VERSION 5.8 ;
NAMESCASESENSITIVE ON ;
BUSBITCHARS "[]" ;
DIVIDERCHAR "/" ;
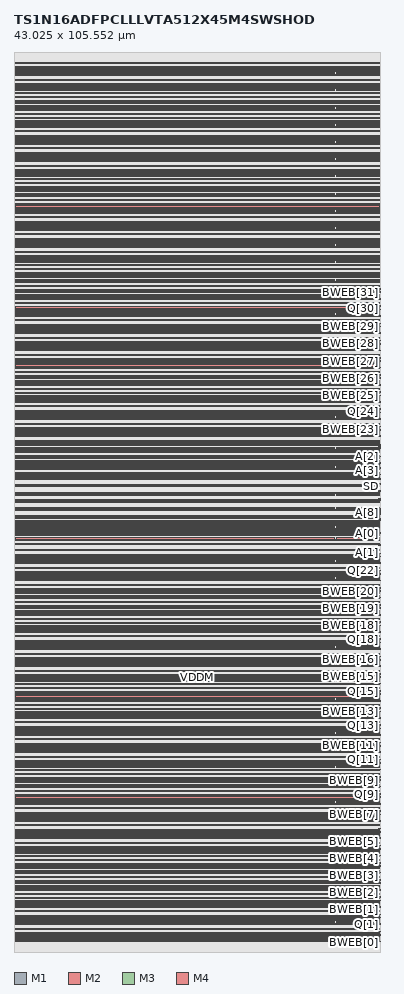
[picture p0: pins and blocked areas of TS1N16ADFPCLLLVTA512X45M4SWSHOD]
MACRO TS1N16ADFPCLLLVTA512X45M4SWSHOD
	CLASS BLOCK ;
	FOREIGN TS1N16ADFPCLLLVTA512X45M4SWSHOD 0.0 0.0 ;
	ORIGIN 0.0 0.0 ;
	SIZE 43.025 BY 105.552 ;
	SYMMETRY X Y ;
	PIN A[0]
		DIRECTION INPUT ;
		USE SIGNAL ;
		PORT
			LAYER M1 ;
			RECT 42.777 49.064 43.025 49.144 ;
			LAYER M2 ;
			RECT 42.777 49.064 43.025 49.144 ;
			LAYER M3 ;
			RECT 42.777 49.064 43.025 49.144 ;
		END
	END A[0]

	PIN A[1]
		DIRECTION INPUT ;
		USE SIGNAL ;
		PORT
			LAYER M1 ;
			RECT 42.777 47.720 43.025 47.800 ;
			LAYER M2 ;
			RECT 42.777 47.720 43.025 47.800 ;
			LAYER M3 ;
			RECT 42.777 47.720 43.025 47.800 ;
		END
	END A[1]

	PIN A[2]
		DIRECTION INPUT ;
		USE SIGNAL ;
		PORT
			LAYER M1 ;
			RECT 42.777 58.088 43.025 58.168 ;
			LAYER M2 ;
			RECT 42.777 58.088 43.025 58.168 ;
			LAYER M3 ;
			RECT 42.777 58.088 43.025 58.168 ;
		END
	END A[2]

	PIN A[3]
		DIRECTION INPUT ;
		USE SIGNAL ;
		PORT
			LAYER M1 ;
			RECT 42.777 57.320 43.025 57.400 ;
			LAYER M2 ;
			RECT 42.777 57.320 43.025 57.400 ;
			LAYER M3 ;
			RECT 42.777 57.320 43.025 57.400 ;
		END
	END A[3]

	PIN A[4]
		DIRECTION INPUT ;
		USE SIGNAL ;
		PORT
			LAYER M1 ;
			RECT 42.777 56.744 43.025 56.824 ;
			LAYER M2 ;
			RECT 42.777 56.744 43.025 56.824 ;
			LAYER M3 ;
			RECT 42.777 56.744 43.025 56.824 ;
		END
	END A[4]

	PIN A[5]
		DIRECTION INPUT ;
		USE SIGNAL ;
		PORT
			LAYER M1 ;
			RECT 42.777 54.056 43.025 54.136 ;
			LAYER M2 ;
			RECT 42.777 54.056 43.025 54.136 ;
			LAYER M3 ;
			RECT 42.777 54.056 43.025 54.136 ;
		END
	END A[5]

	PIN A[6]
		DIRECTION INPUT ;
		USE SIGNAL ;
		PORT
			LAYER M1 ;
			RECT 42.777 54.824 43.025 54.904 ;
			LAYER M2 ;
			RECT 42.777 54.824 43.025 54.904 ;
			LAYER M3 ;
			RECT 42.777 54.824 43.025 54.904 ;
		END
	END A[6]

	PIN A[7]
		DIRECTION INPUT ;
		USE SIGNAL ;
		PORT
			LAYER M1 ;
			RECT 42.777 55.976 43.025 56.056 ;
			LAYER M2 ;
			RECT 42.777 55.976 43.025 56.056 ;
			LAYER M3 ;
			RECT 42.777 55.976 43.025 56.056 ;
		END
	END A[7]

	PIN A[8]
		DIRECTION INPUT ;
		USE SIGNAL ;
		PORT
			LAYER M1 ;
			RECT 42.777 50.600 43.025 50.680 ;
			LAYER M2 ;
			RECT 42.777 50.600 43.025 50.680 ;
			LAYER M3 ;
			RECT 42.777 50.600 43.025 50.680 ;
		END
	END A[8]

	PIN BWEB[0]
		DIRECTION INPUT ;
		USE SIGNAL ;
		PORT
			LAYER M1 ;
			RECT 42.777 1.976 43.025 2.056 ;
			LAYER M2 ;
			RECT 42.777 1.976 43.025 2.056 ;
			LAYER M3 ;
			RECT 42.777 1.976 43.025 2.056 ;
		END
	END BWEB[0]

	PIN BWEB[1]
		DIRECTION INPUT ;
		USE SIGNAL ;
		PORT
			LAYER M1 ;
			RECT 42.777 3.992 43.025 4.072 ;
			LAYER M2 ;
			RECT 42.777 3.992 43.025 4.072 ;
			LAYER M3 ;
			RECT 42.777 3.992 43.025 4.072 ;
		END
	END BWEB[1]

	PIN BWEB[2]
		DIRECTION INPUT ;
		USE SIGNAL ;
		PORT
			LAYER M1 ;
			RECT 42.777 6.008 43.025 6.088 ;
			LAYER M2 ;
			RECT 42.777 6.008 43.025 6.088 ;
			LAYER M3 ;
			RECT 42.777 6.008 43.025 6.088 ;
		END
	END BWEB[2]

	PIN BWEB[3]
		DIRECTION INPUT ;
		USE SIGNAL ;
		PORT
			LAYER M1 ;
			RECT 42.777 8.024 43.025 8.104 ;
			LAYER M2 ;
			RECT 42.777 8.024 43.025 8.104 ;
			LAYER M3 ;
			RECT 42.777 8.024 43.025 8.104 ;
		END
	END BWEB[3]

	PIN BWEB[4]
		DIRECTION INPUT ;
		USE SIGNAL ;
		PORT
			LAYER M1 ;
			RECT 42.777 10.040 43.025 10.120 ;
			LAYER M2 ;
			RECT 42.777 10.040 43.025 10.120 ;
			LAYER M3 ;
			RECT 42.777 10.040 43.025 10.120 ;
		END
	END BWEB[4]

	PIN BWEB[5]
		DIRECTION INPUT ;
		USE SIGNAL ;
		PORT
			LAYER M1 ;
			RECT 42.777 12.056 43.025 12.136 ;
			LAYER M2 ;
			RECT 42.777 12.056 43.025 12.136 ;
			LAYER M3 ;
			RECT 42.777 12.056 43.025 12.136 ;
		END
	END BWEB[5]

	PIN BWEB[6]
		DIRECTION INPUT ;
		USE SIGNAL ;
		PORT
			LAYER M1 ;
			RECT 42.777 14.072 43.025 14.152 ;
			LAYER M2 ;
			RECT 42.777 14.072 43.025 14.152 ;
			LAYER M3 ;
			RECT 42.777 14.072 43.025 14.152 ;
		END
	END BWEB[6]

	PIN BWEB[7]
		DIRECTION INPUT ;
		USE SIGNAL ;
		PORT
			LAYER M1 ;
			RECT 42.777 16.088 43.025 16.168 ;
			LAYER M2 ;
			RECT 42.777 16.088 43.025 16.168 ;
			LAYER M3 ;
			RECT 42.777 16.088 43.025 16.168 ;
		END
	END BWEB[7]

	PIN BWEB[8]
		DIRECTION INPUT ;
		USE SIGNAL ;
		PORT
			LAYER M1 ;
			RECT 42.777 18.104 43.025 18.184 ;
			LAYER M2 ;
			RECT 42.777 18.104 43.025 18.184 ;
			LAYER M3 ;
			RECT 42.777 18.104 43.025 18.184 ;
		END
	END BWEB[8]

	PIN BWEB[9]
		DIRECTION INPUT ;
		USE SIGNAL ;
		PORT
			LAYER M1 ;
			RECT 42.777 20.120 43.025 20.200 ;
			LAYER M2 ;
			RECT 42.777 20.120 43.025 20.200 ;
			LAYER M3 ;
			RECT 42.777 20.120 43.025 20.200 ;
		END
	END BWEB[9]

	PIN BWEB[10]
		DIRECTION INPUT ;
		USE SIGNAL ;
		PORT
			LAYER M1 ;
			RECT 42.777 22.136 43.025 22.216 ;
			LAYER M2 ;
			RECT 42.777 22.136 43.025 22.216 ;
			LAYER M3 ;
			RECT 42.777 22.136 43.025 22.216 ;
		END
	END BWEB[10]

	PIN BWEB[11]
		DIRECTION INPUT ;
		USE SIGNAL ;
		PORT
			LAYER M1 ;
			RECT 42.777 24.152 43.025 24.232 ;
			LAYER M2 ;
			RECT 42.777 24.152 43.025 24.232 ;
			LAYER M3 ;
			RECT 42.777 24.152 43.025 24.232 ;
		END
	END BWEB[11]

	PIN BWEB[12]
		DIRECTION INPUT ;
		USE SIGNAL ;
		PORT
			LAYER M1 ;
			RECT 42.777 26.168 43.025 26.248 ;
			LAYER M2 ;
			RECT 42.777 26.168 43.025 26.248 ;
			LAYER M3 ;
			RECT 42.777 26.168 43.025 26.248 ;
		END
	END BWEB[12]

	PIN BWEB[13]
		DIRECTION INPUT ;
		USE SIGNAL ;
		PORT
			LAYER M1 ;
			RECT 42.777 28.184 43.025 28.264 ;
			LAYER M2 ;
			RECT 42.777 28.184 43.025 28.264 ;
			LAYER M3 ;
			RECT 42.777 28.184 43.025 28.264 ;
		END
	END BWEB[13]

	PIN BWEB[14]
		DIRECTION INPUT ;
		USE SIGNAL ;
		PORT
			LAYER M1 ;
			RECT 42.777 30.200 43.025 30.280 ;
			LAYER M2 ;
			RECT 42.777 30.200 43.025 30.280 ;
			LAYER M3 ;
			RECT 42.777 30.200 43.025 30.280 ;
		END
	END BWEB[14]

	PIN BWEB[15]
		DIRECTION INPUT ;
		USE SIGNAL ;
		PORT
			LAYER M1 ;
			RECT 42.777 32.216 43.025 32.296 ;
			LAYER M2 ;
			RECT 42.777 32.216 43.025 32.296 ;
			LAYER M3 ;
			RECT 42.777 32.216 43.025 32.296 ;
		END
	END BWEB[15]

	PIN BWEB[16]
		DIRECTION INPUT ;
		USE SIGNAL ;
		PORT
			LAYER M1 ;
			RECT 42.777 34.232 43.025 34.312 ;
			LAYER M2 ;
			RECT 42.777 34.232 43.025 34.312 ;
			LAYER M3 ;
			RECT 42.777 34.232 43.025 34.312 ;
		END
	END BWEB[16]

	PIN BWEB[17]
		DIRECTION INPUT ;
		USE SIGNAL ;
		PORT
			LAYER M1 ;
			RECT 42.777 36.248 43.025 36.328 ;
			LAYER M2 ;
			RECT 42.777 36.248 43.025 36.328 ;
			LAYER M3 ;
			RECT 42.777 36.248 43.025 36.328 ;
		END
	END BWEB[17]

	PIN BWEB[18]
		DIRECTION INPUT ;
		USE SIGNAL ;
		PORT
			LAYER M1 ;
			RECT 42.777 38.264 43.025 38.344 ;
			LAYER M2 ;
			RECT 42.777 38.264 43.025 38.344 ;
			LAYER M3 ;
			RECT 42.777 38.264 43.025 38.344 ;
		END
	END BWEB[18]

	PIN BWEB[19]
		DIRECTION INPUT ;
		USE SIGNAL ;
		PORT
			LAYER M1 ;
			RECT 42.777 40.280 43.025 40.360 ;
			LAYER M2 ;
			RECT 42.777 40.280 43.025 40.360 ;
			LAYER M3 ;
			RECT 42.777 40.280 43.025 40.360 ;
		END
	END BWEB[19]

	PIN BWEB[20]
		DIRECTION INPUT ;
		USE SIGNAL ;
		PORT
			LAYER M1 ;
			RECT 42.777 42.296 43.025 42.376 ;
			LAYER M2 ;
			RECT 42.777 42.296 43.025 42.376 ;
			LAYER M3 ;
			RECT 42.777 42.296 43.025 42.376 ;
		END
	END BWEB[20]

	PIN BWEB[21]
		DIRECTION INPUT ;
		USE SIGNAL ;
		PORT
			LAYER M1 ;
			RECT 42.777 44.312 43.025 44.392 ;
			LAYER M2 ;
			RECT 42.777 44.312 43.025 44.392 ;
			LAYER M3 ;
			RECT 42.777 44.312 43.025 44.392 ;
		END
	END BWEB[21]

	PIN BWEB[22]
		DIRECTION INPUT ;
		USE SIGNAL ;
		PORT
			LAYER M1 ;
			RECT 42.777 46.328 43.025 46.408 ;
			LAYER M2 ;
			RECT 42.777 46.328 43.025 46.408 ;
			LAYER M3 ;
			RECT 42.777 46.328 43.025 46.408 ;
		END
	END BWEB[22]

	PIN BWEB[23]
		DIRECTION INPUT ;
		USE SIGNAL ;
		PORT
			LAYER M1 ;
			RECT 42.777 61.208 43.025 61.288 ;
			LAYER M2 ;
			RECT 42.777 61.208 43.025 61.288 ;
			LAYER M3 ;
			RECT 42.777 61.208 43.025 61.288 ;
		END
	END BWEB[23]

	PIN BWEB[24]
		DIRECTION INPUT ;
		USE SIGNAL ;
		PORT
			LAYER M1 ;
			RECT 42.777 63.224 43.025 63.304 ;
			LAYER M2 ;
			RECT 42.777 63.224 43.025 63.304 ;
			LAYER M3 ;
			RECT 42.777 63.224 43.025 63.304 ;
		END
	END BWEB[24]

	PIN BWEB[25]
		DIRECTION INPUT ;
		USE SIGNAL ;
		PORT
			LAYER M1 ;
			RECT 42.777 65.240 43.025 65.320 ;
			LAYER M2 ;
			RECT 42.777 65.240 43.025 65.320 ;
			LAYER M3 ;
			RECT 42.777 65.240 43.025 65.320 ;
		END
	END BWEB[25]

	PIN BWEB[26]
		DIRECTION INPUT ;
		USE SIGNAL ;
		PORT
			LAYER M1 ;
			RECT 42.777 67.256 43.025 67.336 ;
			LAYER M2 ;
			RECT 42.777 67.256 43.025 67.336 ;
			LAYER M3 ;
			RECT 42.777 67.256 43.025 67.336 ;
		END
	END BWEB[26]

	PIN BWEB[27]
		DIRECTION INPUT ;
		USE SIGNAL ;
		PORT
			LAYER M1 ;
			RECT 42.777 69.272 43.025 69.352 ;
			LAYER M2 ;
			RECT 42.777 69.272 43.025 69.352 ;
			LAYER M3 ;
			RECT 42.777 69.272 43.025 69.352 ;
		END
	END BWEB[27]

	PIN BWEB[28]
		DIRECTION INPUT ;
		USE SIGNAL ;
		PORT
			LAYER M1 ;
			RECT 42.777 71.288 43.025 71.368 ;
			LAYER M2 ;
			RECT 42.777 71.288 43.025 71.368 ;
			LAYER M3 ;
			RECT 42.777 71.288 43.025 71.368 ;
		END
	END BWEB[28]

	PIN BWEB[29]
		DIRECTION INPUT ;
		USE SIGNAL ;
		PORT
			LAYER M1 ;
			RECT 42.777 73.304 43.025 73.384 ;
			LAYER M2 ;
			RECT 42.777 73.304 43.025 73.384 ;
			LAYER M3 ;
			RECT 42.777 73.304 43.025 73.384 ;
		END
	END BWEB[29]

	PIN BWEB[30]
		DIRECTION INPUT ;
		USE SIGNAL ;
		PORT
			LAYER M1 ;
			RECT 42.777 75.320 43.025 75.400 ;
			LAYER M2 ;
			RECT 42.777 75.320 43.025 75.400 ;
			LAYER M3 ;
			RECT 42.777 75.320 43.025 75.400 ;
		END
	END BWEB[30]

	PIN BWEB[31]
		DIRECTION INPUT ;
		USE SIGNAL ;
		PORT
			LAYER M1 ;
			RECT 42.777 77.336 43.025 77.416 ;
			LAYER M2 ;
			RECT 42.777 77.336 43.025 77.416 ;
			LAYER M3 ;
			RECT 42.777 77.336 43.025 77.416 ;
		END
	END BWEB[31]














	PIN CEB
		DIRECTION INPUT ;
		USE SIGNAL ;
		PORT
			LAYER M1 ;
			RECT 42.777 50.792 43.025 50.872 ;
			LAYER M2 ;
			RECT 42.777 50.792 43.025 50.872 ;
			LAYER M3 ;
			RECT 42.777 50.792 43.025 50.872 ;
		END
	END CEB

	PIN CLK
		DIRECTION INPUT ;
		USE SIGNAL ;
		PORT
			LAYER M1 ;
			RECT 42.777 53.096 43.025 53.176 ;
			LAYER M2 ;
			RECT 42.777 53.096 43.025 53.176 ;
			LAYER M3 ;
			RECT 42.777 53.096 43.025 53.176 ;
		END
	END CLK

	PIN D[0]
		DIRECTION INPUT ;
		USE SIGNAL ;
		PORT
			LAYER M1 ;
			RECT 42.777 2.360 43.025 2.440 ;
			LAYER M2 ;
			RECT 42.777 2.360 43.025 2.440 ;
			LAYER M3 ;
			RECT 42.777 2.360 43.025 2.440 ;
		END
	END D[0]

	PIN D[1]
		DIRECTION INPUT ;
		USE SIGNAL ;
		PORT
			LAYER M1 ;
			RECT 42.777 4.376 43.025 4.456 ;
			LAYER M2 ;
			RECT 42.777 4.376 43.025 4.456 ;
			LAYER M3 ;
			RECT 42.777 4.376 43.025 4.456 ;
		END
	END D[1]

	PIN D[2]
		DIRECTION INPUT ;
		USE SIGNAL ;
		PORT
			LAYER M1 ;
			RECT 42.777 6.392 43.025 6.472 ;
			LAYER M2 ;
			RECT 42.777 6.392 43.025 6.472 ;
			LAYER M3 ;
			RECT 42.777 6.392 43.025 6.472 ;
		END
	END D[2]

	PIN D[3]
		DIRECTION INPUT ;
		USE SIGNAL ;
		PORT
			LAYER M1 ;
			RECT 42.777 8.408 43.025 8.488 ;
			LAYER M2 ;
			RECT 42.777 8.408 43.025 8.488 ;
			LAYER M3 ;
			RECT 42.777 8.408 43.025 8.488 ;
		END
	END D[3]

	PIN D[4]
		DIRECTION INPUT ;
		USE SIGNAL ;
		PORT
			LAYER M1 ;
			RECT 42.777 10.424 43.025 10.504 ;
			LAYER M2 ;
			RECT 42.777 10.424 43.025 10.504 ;
			LAYER M3 ;
			RECT 42.777 10.424 43.025 10.504 ;
		END
	END D[4]

	PIN D[5]
		DIRECTION INPUT ;
		USE SIGNAL ;
		PORT
			LAYER M1 ;
			RECT 42.777 12.440 43.025 12.520 ;
			LAYER M2 ;
			RECT 42.777 12.440 43.025 12.520 ;
			LAYER M3 ;
			RECT 42.777 12.440 43.025 12.520 ;
		END
	END D[5]

	PIN D[6]
		DIRECTION INPUT ;
		USE SIGNAL ;
		PORT
			LAYER M1 ;
			RECT 42.777 14.456 43.025 14.536 ;
			LAYER M2 ;
			RECT 42.777 14.456 43.025 14.536 ;
			LAYER M3 ;
			RECT 42.777 14.456 43.025 14.536 ;
		END
	END D[6]

	PIN D[7]
		DIRECTION INPUT ;
		USE SIGNAL ;
		PORT
			LAYER M1 ;
			RECT 42.777 16.472 43.025 16.552 ;
			LAYER M2 ;
			RECT 42.777 16.472 43.025 16.552 ;
			LAYER M3 ;
			RECT 42.777 16.472 43.025 16.552 ;
		END
	END D[7]

	PIN D[8]
		DIRECTION INPUT ;
		USE SIGNAL ;
		PORT
			LAYER M1 ;
			RECT 42.777 18.488 43.025 18.568 ;
			LAYER M2 ;
			RECT 42.777 18.488 43.025 18.568 ;
			LAYER M3 ;
			RECT 42.777 18.488 43.025 18.568 ;
		END
	END D[8]

	PIN D[9]
		DIRECTION INPUT ;
		USE SIGNAL ;
		PORT
			LAYER M1 ;
			RECT 42.777 20.504 43.025 20.584 ;
			LAYER M2 ;
			RECT 42.777 20.504 43.025 20.584 ;
			LAYER M3 ;
			RECT 42.777 20.504 43.025 20.584 ;
		END
	END D[9]

	PIN D[10]
		DIRECTION INPUT ;
		USE SIGNAL ;
		PORT
			LAYER M1 ;
			RECT 42.777 22.520 43.025 22.600 ;
			LAYER M2 ;
			RECT 42.777 22.520 43.025 22.600 ;
			LAYER M3 ;
			RECT 42.777 22.520 43.025 22.600 ;
		END
	END D[10]

	PIN D[11]
		DIRECTION INPUT ;
		USE SIGNAL ;
		PORT
			LAYER M1 ;
			RECT 42.777 24.536 43.025 24.616 ;
			LAYER M2 ;
			RECT 42.777 24.536 43.025 24.616 ;
			LAYER M3 ;
			RECT 42.777 24.536 43.025 24.616 ;
		END
	END D[11]

	PIN D[12]
		DIRECTION INPUT ;
		USE SIGNAL ;
		PORT
			LAYER M1 ;
			RECT 42.777 26.552 43.025 26.632 ;
			LAYER M2 ;
			RECT 42.777 26.552 43.025 26.632 ;
			LAYER M3 ;
			RECT 42.777 26.552 43.025 26.632 ;
		END
	END D[12]

	PIN D[13]
		DIRECTION INPUT ;
		USE SIGNAL ;
		PORT
			LAYER M1 ;
			RECT 42.777 28.568 43.025 28.648 ;
			LAYER M2 ;
			RECT 42.777 28.568 43.025 28.648 ;
			LAYER M3 ;
			RECT 42.777 28.568 43.025 28.648 ;
		END
	END D[13]

	PIN D[14]
		DIRECTION INPUT ;
		USE SIGNAL ;
		PORT
			LAYER M1 ;
			RECT 42.777 30.584 43.025 30.664 ;
			LAYER M2 ;
			RECT 42.777 30.584 43.025 30.664 ;
			LAYER M3 ;
			RECT 42.777 30.584 43.025 30.664 ;
		END
	END D[14]

	PIN D[15]
		DIRECTION INPUT ;
		USE SIGNAL ;
		PORT
			LAYER M1 ;
			RECT 42.777 32.600 43.025 32.680 ;
			LAYER M2 ;
			RECT 42.777 32.600 43.025 32.680 ;
			LAYER M3 ;
			RECT 42.777 32.600 43.025 32.680 ;
		END
	END D[15]

	PIN D[16]
		DIRECTION INPUT ;
		USE SIGNAL ;
		PORT
			LAYER M1 ;
			RECT 42.777 34.616 43.025 34.696 ;
			LAYER M2 ;
			RECT 42.777 34.616 43.025 34.696 ;
			LAYER M3 ;
			RECT 42.777 34.616 43.025 34.696 ;
		END
	END D[16]

	PIN D[17]
		DIRECTION INPUT ;
		USE SIGNAL ;
		PORT
			LAYER M1 ;
			RECT 42.777 36.632 43.025 36.712 ;
			LAYER M2 ;
			RECT 42.777 36.632 43.025 36.712 ;
			LAYER M3 ;
			RECT 42.777 36.632 43.025 36.712 ;
		END
	END D[17]

	PIN D[18]
		DIRECTION INPUT ;
		USE SIGNAL ;
		PORT
			LAYER M1 ;
			RECT 42.777 38.648 43.025 38.728 ;
			LAYER M2 ;
			RECT 42.777 38.648 43.025 38.728 ;
			LAYER M3 ;
			RECT 42.777 38.648 43.025 38.728 ;
		END
	END D[18]

	PIN D[19]
		DIRECTION INPUT ;
		USE SIGNAL ;
		PORT
			LAYER M1 ;
			RECT 42.777 40.664 43.025 40.744 ;
			LAYER M2 ;
			RECT 42.777 40.664 43.025 40.744 ;
			LAYER M3 ;
			RECT 42.777 40.664 43.025 40.744 ;
		END
	END D[19]

	PIN D[20]
		DIRECTION INPUT ;
		USE SIGNAL ;
		PORT
			LAYER M1 ;
			RECT 42.777 42.680 43.025 42.760 ;
			LAYER M2 ;
			RECT 42.777 42.680 43.025 42.760 ;
			LAYER M3 ;
			RECT 42.777 42.680 43.025 42.760 ;
		END
	END D[20]

	PIN D[21]
		DIRECTION INPUT ;
		USE SIGNAL ;
		PORT
			LAYER M1 ;
			RECT 42.777 44.696 43.025 44.776 ;
			LAYER M2 ;
			RECT 42.777 44.696 43.025 44.776 ;
			LAYER M3 ;
			RECT 42.777 44.696 43.025 44.776 ;
		END
	END D[21]

	PIN D[22]
		DIRECTION INPUT ;
		USE SIGNAL ;
		PORT
			LAYER M1 ;
			RECT 42.777 46.712 43.025 46.792 ;
			LAYER M2 ;
			RECT 42.777 46.712 43.025 46.792 ;
			LAYER M3 ;
			RECT 42.777 46.712 43.025 46.792 ;
		END
	END D[22]

	PIN D[23]
		DIRECTION INPUT ;
		USE SIGNAL ;
		PORT
			LAYER M1 ;
			RECT 42.777 61.592 43.025 61.672 ;
			LAYER M2 ;
			RECT 42.777 61.592 43.025 61.672 ;
			LAYER M3 ;
			RECT 42.777 61.592 43.025 61.672 ;
		END
	END D[23]

	PIN D[24]
		DIRECTION INPUT ;
		USE SIGNAL ;
		PORT
			LAYER M1 ;
			RECT 42.777 63.608 43.025 63.688 ;
			LAYER M2 ;
			RECT 42.777 63.608 43.025 63.688 ;
			LAYER M3 ;
			RECT 42.777 63.608 43.025 63.688 ;
		END
	END D[24]

	PIN D[25]
		DIRECTION INPUT ;
		USE SIGNAL ;
		PORT
			LAYER M1 ;
			RECT 42.777 65.624 43.025 65.704 ;
			LAYER M2 ;
			RECT 42.777 65.624 43.025 65.704 ;
			LAYER M3 ;
			RECT 42.777 65.624 43.025 65.704 ;
		END
	END D[25]

	PIN D[26]
		DIRECTION INPUT ;
		USE SIGNAL ;
		PORT
			LAYER M1 ;
			RECT 42.777 67.640 43.025 67.720 ;
			LAYER M2 ;
			RECT 42.777 67.640 43.025 67.720 ;
			LAYER M3 ;
			RECT 42.777 67.640 43.025 67.720 ;
		END
	END D[26]

	PIN D[27]
		DIRECTION INPUT ;
		USE SIGNAL ;
		PORT
			LAYER M1 ;
			RECT 42.777 69.656 43.025 69.736 ;
			LAYER M2 ;
			RECT 42.777 69.656 43.025 69.736 ;
			LAYER M3 ;
			RECT 42.777 69.656 43.025 69.736 ;
		END
	END D[27]

	PIN D[28]
		DIRECTION INPUT ;
		USE SIGNAL ;
		PORT
			LAYER M1 ;
			RECT 42.777 71.672 43.025 71.752 ;
			LAYER M2 ;
			RECT 42.777 71.672 43.025 71.752 ;
			LAYER M3 ;
			RECT 42.777 71.672 43.025 71.752 ;
		END
	END D[28]

	PIN D[29]
		DIRECTION INPUT ;
		USE SIGNAL ;
		PORT
			LAYER M1 ;
			RECT 42.777 73.688 43.025 73.768 ;
			LAYER M2 ;
			RECT 42.777 73.688 43.025 73.768 ;
			LAYER M3 ;
			RECT 42.777 73.688 43.025 73.768 ;
		END
	END D[29]

	PIN D[30]
		DIRECTION INPUT ;
		USE SIGNAL ;
		PORT
			LAYER M1 ;
			RECT 42.777 75.704 43.025 75.784 ;
			LAYER M2 ;
			RECT 42.777 75.704 43.025 75.784 ;
			LAYER M3 ;
			RECT 42.777 75.704 43.025 75.784 ;
		END
	END D[30]

	PIN D[31]
		DIRECTION INPUT ;
		USE SIGNAL ;
		PORT
			LAYER M1 ;
			RECT 42.777 77.720 43.025 77.800 ;
			LAYER M2 ;
			RECT 42.777 77.720 43.025 77.800 ;
			LAYER M3 ;
			RECT 42.777 77.720 43.025 77.800 ;
		END
	END D[31]














	PIN DSLP
		DIRECTION INPUT ;
		USE SIGNAL ;
		PORT
			LAYER M1 ;
			RECT 42.777 51.368 43.025 51.448 ;
			LAYER M2 ;
			RECT 42.777 51.368 43.025 51.448 ;
			LAYER M3 ;
			RECT 42.777 51.368 43.025 51.448 ;
		END
	END DSLP

	PIN PUDELAY
		DIRECTION OUTPUT ;
		USE SIGNAL ;
		PORT
			LAYER M1 ;
			RECT 42.777 59.432 43.025 59.512 ;
			LAYER M2 ;
			RECT 42.777 59.432 43.025 59.512 ;
			LAYER M3 ;
			RECT 42.777 59.432 43.025 59.512 ;
		END
	END PUDELAY

	PIN Q[0]
		DIRECTION OUTPUT ;
		USE SIGNAL ;
		PORT
			LAYER M1 ;
			RECT 42.777 1.208 43.025 1.288 ;
			LAYER M2 ;
			RECT 42.777 1.208 43.025 1.288 ;
			LAYER M3 ;
			RECT 42.777 1.208 43.025 1.288 ;
		END
	END Q[0]

	PIN Q[1]
		DIRECTION OUTPUT ;
		USE SIGNAL ;
		PORT
			LAYER M1 ;
			RECT 42.777 3.224 43.025 3.304 ;
			LAYER M2 ;
			RECT 42.777 3.224 43.025 3.304 ;
			LAYER M3 ;
			RECT 42.777 3.224 43.025 3.304 ;
		END
	END Q[1]

	PIN Q[2]
		DIRECTION OUTPUT ;
		USE SIGNAL ;
		PORT
			LAYER M1 ;
			RECT 42.777 5.240 43.025 5.320 ;
			LAYER M2 ;
			RECT 42.777 5.240 43.025 5.320 ;
			LAYER M3 ;
			RECT 42.777 5.240 43.025 5.320 ;
		END
	END Q[2]

	PIN Q[3]
		DIRECTION OUTPUT ;
		USE SIGNAL ;
		PORT
			LAYER M1 ;
			RECT 42.777 7.256 43.025 7.336 ;
			LAYER M2 ;
			RECT 42.777 7.256 43.025 7.336 ;
			LAYER M3 ;
			RECT 42.777 7.256 43.025 7.336 ;
		END
	END Q[3]

	PIN Q[4]
		DIRECTION OUTPUT ;
		USE SIGNAL ;
		PORT
			LAYER M1 ;
			RECT 42.777 9.272 43.025 9.352 ;
			LAYER M2 ;
			RECT 42.777 9.272 43.025 9.352 ;
			LAYER M3 ;
			RECT 42.777 9.272 43.025 9.352 ;
		END
	END Q[4]

	PIN Q[5]
		DIRECTION OUTPUT ;
		USE SIGNAL ;
		PORT
			LAYER M1 ;
			RECT 42.777 11.288 43.025 11.368 ;
			LAYER M2 ;
			RECT 42.777 11.288 43.025 11.368 ;
			LAYER M3 ;
			RECT 42.777 11.288 43.025 11.368 ;
		END
	END Q[5]

	PIN Q[6]
		DIRECTION OUTPUT ;
		USE SIGNAL ;
		PORT
			LAYER M1 ;
			RECT 42.777 13.304 43.025 13.384 ;
			LAYER M2 ;
			RECT 42.777 13.304 43.025 13.384 ;
			LAYER M3 ;
			RECT 42.777 13.304 43.025 13.384 ;
		END
	END Q[6]

	PIN Q[7]
		DIRECTION OUTPUT ;
		USE SIGNAL ;
		PORT
			LAYER M1 ;
			RECT 42.777 15.320 43.025 15.400 ;
			LAYER M2 ;
			RECT 42.777 15.320 43.025 15.400 ;
			LAYER M3 ;
			RECT 42.777 15.320 43.025 15.400 ;
		END
	END Q[7]

	PIN Q[8]
		DIRECTION OUTPUT ;
		USE SIGNAL ;
		PORT
			LAYER M1 ;
			RECT 42.777 17.336 43.025 17.416 ;
			LAYER M2 ;
			RECT 42.777 17.336 43.025 17.416 ;
			LAYER M3 ;
			RECT 42.777 17.336 43.025 17.416 ;
		END
	END Q[8]

	PIN Q[9]
		DIRECTION OUTPUT ;
		USE SIGNAL ;
		PORT
			LAYER M1 ;
			RECT 42.777 19.352 43.025 19.432 ;
			LAYER M2 ;
			RECT 42.777 19.352 43.025 19.432 ;
			LAYER M3 ;
			RECT 42.777 19.352 43.025 19.432 ;
		END
	END Q[9]

	PIN Q[10]
		DIRECTION OUTPUT ;
		USE SIGNAL ;
		PORT
			LAYER M1 ;
			RECT 42.777 21.368 43.025 21.448 ;
			LAYER M2 ;
			RECT 42.777 21.368 43.025 21.448 ;
			LAYER M3 ;
			RECT 42.777 21.368 43.025 21.448 ;
		END
	END Q[10]

	PIN Q[11]
		DIRECTION OUTPUT ;
		USE SIGNAL ;
		PORT
			LAYER M1 ;
			RECT 42.777 23.384 43.025 23.464 ;
			LAYER M2 ;
			RECT 42.777 23.384 43.025 23.464 ;
			LAYER M3 ;
			RECT 42.777 23.384 43.025 23.464 ;
		END
	END Q[11]

	PIN Q[12]
		DIRECTION OUTPUT ;
		USE SIGNAL ;
		PORT
			LAYER M1 ;
			RECT 42.777 25.400 43.025 25.480 ;
			LAYER M2 ;
			RECT 42.777 25.400 43.025 25.480 ;
			LAYER M3 ;
			RECT 42.777 25.400 43.025 25.480 ;
		END
	END Q[12]

	PIN Q[13]
		DIRECTION OUTPUT ;
		USE SIGNAL ;
		PORT
			LAYER M1 ;
			RECT 42.777 27.416 43.025 27.496 ;
			LAYER M2 ;
			RECT 42.777 27.416 43.025 27.496 ;
			LAYER M3 ;
			RECT 42.777 27.416 43.025 27.496 ;
		END
	END Q[13]

	PIN Q[14]
		DIRECTION OUTPUT ;
		USE SIGNAL ;
		PORT
			LAYER M1 ;
			RECT 42.777 29.432 43.025 29.512 ;
			LAYER M2 ;
			RECT 42.777 29.432 43.025 29.512 ;
			LAYER M3 ;
			RECT 42.777 29.432 43.025 29.512 ;
		END
	END Q[14]

	PIN Q[15]
		DIRECTION OUTPUT ;
		USE SIGNAL ;
		PORT
			LAYER M1 ;
			RECT 42.777 31.448 43.025 31.528 ;
			LAYER M2 ;
			RECT 42.777 31.448 43.025 31.528 ;
			LAYER M3 ;
			RECT 42.777 31.448 43.025 31.528 ;
		END
	END Q[15]

	PIN Q[16]
		DIRECTION OUTPUT ;
		USE SIGNAL ;
		PORT
			LAYER M1 ;
			RECT 42.777 33.464 43.025 33.544 ;
			LAYER M2 ;
			RECT 42.777 33.464 43.025 33.544 ;
			LAYER M3 ;
			RECT 42.777 33.464 43.025 33.544 ;
		END
	END Q[16]

	PIN Q[17]
		DIRECTION OUTPUT ;
		USE SIGNAL ;
		PORT
			LAYER M1 ;
			RECT 42.777 35.480 43.025 35.560 ;
			LAYER M2 ;
			RECT 42.777 35.480 43.025 35.560 ;
			LAYER M3 ;
			RECT 42.777 35.480 43.025 35.560 ;
		END
	END Q[17]

	PIN Q[18]
		DIRECTION OUTPUT ;
		USE SIGNAL ;
		PORT
			LAYER M1 ;
			RECT 42.777 37.496 43.025 37.576 ;
			LAYER M2 ;
			RECT 42.777 37.496 43.025 37.576 ;
			LAYER M3 ;
			RECT 42.777 37.496 43.025 37.576 ;
		END
	END Q[18]

	PIN Q[19]
		DIRECTION OUTPUT ;
		USE SIGNAL ;
		PORT
			LAYER M1 ;
			RECT 42.777 39.512 43.025 39.592 ;
			LAYER M2 ;
			RECT 42.777 39.512 43.025 39.592 ;
			LAYER M3 ;
			RECT 42.777 39.512 43.025 39.592 ;
		END
	END Q[19]

	PIN Q[20]
		DIRECTION OUTPUT ;
		USE SIGNAL ;
		PORT
			LAYER M1 ;
			RECT 42.777 41.528 43.025 41.608 ;
			LAYER M2 ;
			RECT 42.777 41.528 43.025 41.608 ;
			LAYER M3 ;
			RECT 42.777 41.528 43.025 41.608 ;
		END
	END Q[20]

	PIN Q[21]
		DIRECTION OUTPUT ;
		USE SIGNAL ;
		PORT
			LAYER M1 ;
			RECT 42.777 43.544 43.025 43.624 ;
			LAYER M2 ;
			RECT 42.777 43.544 43.025 43.624 ;
			LAYER M3 ;
			RECT 42.777 43.544 43.025 43.624 ;
		END
	END Q[21]

	PIN Q[22]
		DIRECTION OUTPUT ;
		USE SIGNAL ;
		PORT
			LAYER M1 ;
			RECT 42.777 45.560 43.025 45.640 ;
			LAYER M2 ;
			RECT 42.777 45.560 43.025 45.640 ;
			LAYER M3 ;
			RECT 42.777 45.560 43.025 45.640 ;
		END
	END Q[22]

	PIN Q[23]
		DIRECTION OUTPUT ;
		USE SIGNAL ;
		PORT
			LAYER M1 ;
			RECT 42.777 60.440 43.025 60.520 ;
			LAYER M2 ;
			RECT 42.777 60.440 43.025 60.520 ;
			LAYER M3 ;
			RECT 42.777 60.440 43.025 60.520 ;
		END
	END Q[23]

	PIN Q[24]
		DIRECTION OUTPUT ;
		USE SIGNAL ;
		PORT
			LAYER M1 ;
			RECT 42.777 62.456 43.025 62.536 ;
			LAYER M2 ;
			RECT 42.777 62.456 43.025 62.536 ;
			LAYER M3 ;
			RECT 42.777 62.456 43.025 62.536 ;
		END
	END Q[24]

	PIN Q[25]
		DIRECTION OUTPUT ;
		USE SIGNAL ;
		PORT
			LAYER M1 ;
			RECT 42.777 64.472 43.025 64.552 ;
			LAYER M2 ;
			RECT 42.777 64.472 43.025 64.552 ;
			LAYER M3 ;
			RECT 42.777 64.472 43.025 64.552 ;
		END
	END Q[25]

	PIN Q[26]
		DIRECTION OUTPUT ;
		USE SIGNAL ;
		PORT
			LAYER M1 ;
			RECT 42.777 66.488 43.025 66.568 ;
			LAYER M2 ;
			RECT 42.777 66.488 43.025 66.568 ;
			LAYER M3 ;
			RECT 42.777 66.488 43.025 66.568 ;
		END
	END Q[26]

	PIN Q[27]
		DIRECTION OUTPUT ;
		USE SIGNAL ;
		PORT
			LAYER M1 ;
			RECT 42.777 68.504 43.025 68.584 ;
			LAYER M2 ;
			RECT 42.777 68.504 43.025 68.584 ;
			LAYER M3 ;
			RECT 42.777 68.504 43.025 68.584 ;
		END
	END Q[27]

	PIN Q[28]
		DIRECTION OUTPUT ;
		USE SIGNAL ;
		PORT
			LAYER M1 ;
			RECT 42.777 70.520 43.025 70.600 ;
			LAYER M2 ;
			RECT 42.777 70.520 43.025 70.600 ;
			LAYER M3 ;
			RECT 42.777 70.520 43.025 70.600 ;
		END
	END Q[28]

	PIN Q[29]
		DIRECTION OUTPUT ;
		USE SIGNAL ;
		PORT
			LAYER M1 ;
			RECT 42.777 72.536 43.025 72.616 ;
			LAYER M2 ;
			RECT 42.777 72.536 43.025 72.616 ;
			LAYER M3 ;
			RECT 42.777 72.536 43.025 72.616 ;
		END
	END Q[29]

	PIN Q[30]
		DIRECTION OUTPUT ;
		USE SIGNAL ;
		PORT
			LAYER M1 ;
			RECT 42.777 74.552 43.025 74.632 ;
			LAYER M2 ;
			RECT 42.777 74.552 43.025 74.632 ;
			LAYER M3 ;
			RECT 42.777 74.552 43.025 74.632 ;
		END
	END Q[30]

	PIN Q[31]
		DIRECTION OUTPUT ;
		USE SIGNAL ;
		PORT
			LAYER M1 ;
			RECT 42.777 76.568 43.025 76.648 ;
			LAYER M2 ;
			RECT 42.777 76.568 43.025 76.648 ;
			LAYER M3 ;
			RECT 42.777 76.568 43.025 76.648 ;
		END
	END Q[31]














	PIN RTSEL[0]
		DIRECTION INPUT ;
		USE SIGNAL ;
		PORT
			LAYER M1 ;
			RECT 42.777 59.048 43.025 59.128 ;
			LAYER M2 ;
			RECT 42.777 59.048 43.025 59.128 ;
			LAYER M3 ;
			RECT 42.777 59.048 43.025 59.128 ;
		END
	END RTSEL[0]

	PIN RTSEL[1]
		DIRECTION INPUT ;
		USE SIGNAL ;
		PORT
			LAYER M1 ;
			RECT 42.777 59.240 43.025 59.320 ;
			LAYER M2 ;
			RECT 42.777 59.240 43.025 59.320 ;
			LAYER M3 ;
			RECT 42.777 59.240 43.025 59.320 ;
		END
	END RTSEL[1]

	PIN SD
		DIRECTION INPUT ;
		USE SIGNAL ;
		PORT
			LAYER M1 ;
			RECT 42.777 55.400 43.025 55.480 ;
			LAYER M2 ;
			RECT 42.777 55.400 43.025 55.480 ;
			LAYER M3 ;
			RECT 42.777 55.400 43.025 55.480 ;
		END
	END SD

	PIN SLP
		DIRECTION INPUT ;
		USE SIGNAL ;
		PORT
			LAYER M1 ;
			RECT 42.777 51.560 43.025 51.640 ;
			LAYER M2 ;
			RECT 42.777 51.560 43.025 51.640 ;
			LAYER M3 ;
			RECT 42.777 51.560 43.025 51.640 ;
		END
	END SLP

	PIN VDD
		DIRECTION INOUT ;
		USE POWER ;
		PORT
			LAYER M4 ;
			RECT 37.773 1.428 42.905 1.548 ;
			LAYER M4 ;
			RECT 37.773 3.444 42.905 3.564 ;
			LAYER M4 ;
			RECT 37.773 5.460 42.905 5.580 ;
			LAYER M4 ;
			RECT 37.773 7.476 42.905 7.596 ;
			LAYER M4 ;
			RECT 37.773 9.492 42.905 9.612 ;
			LAYER M4 ;
			RECT 37.773 11.508 42.905 11.628 ;
			LAYER M4 ;
			RECT 37.773 13.524 42.905 13.644 ;
			LAYER M4 ;
			RECT 37.773 15.540 42.905 15.660 ;
			LAYER M4 ;
			RECT 37.773 17.556 42.905 17.676 ;
			LAYER M4 ;
			RECT 37.773 19.572 42.905 19.692 ;
			LAYER M4 ;
			RECT 37.773 21.588 42.905 21.708 ;
			LAYER M4 ;
			RECT 37.773 23.604 42.905 23.724 ;
			LAYER M4 ;
			RECT 37.773 25.620 42.905 25.740 ;
			LAYER M4 ;
			RECT 37.773 27.636 42.905 27.756 ;
			LAYER M4 ;
			RECT 37.773 29.652 42.905 29.772 ;
			LAYER M4 ;
			RECT 37.773 31.668 42.905 31.788 ;
			LAYER M4 ;
			RECT 37.773 33.684 42.905 33.804 ;
			LAYER M4 ;
			RECT 37.773 35.700 42.905 35.820 ;
			LAYER M4 ;
			RECT 37.773 37.716 42.905 37.836 ;
			LAYER M4 ;
			RECT 37.773 39.732 42.905 39.852 ;
			LAYER M4 ;
			RECT 37.773 41.748 42.905 41.868 ;
			LAYER M4 ;
			RECT 37.773 43.764 42.905 43.884 ;
			LAYER M4 ;
			RECT 37.773 45.780 42.905 45.900 ;
			LAYER M4 ;
			RECT 37.773 48.436 42.905 48.556 ;
			LAYER M4 ;
			RECT 37.773 49.762 42.905 49.882 ;
			LAYER M4 ;
			RECT 37.773 51.994 42.905 52.114 ;
			LAYER M4 ;
			RECT 37.773 53.588 42.905 53.708 ;
			LAYER M4 ;
			RECT 37.773 56.792 42.905 56.912 ;
			LAYER M4 ;
			RECT 37.773 59.014 42.905 59.134 ;
			LAYER M4 ;
			RECT 37.773 60.660 42.905 60.780 ;
			LAYER M4 ;
			RECT 37.773 62.676 42.905 62.796 ;
			LAYER M4 ;
			RECT 37.773 64.692 42.905 64.812 ;
			LAYER M4 ;
			RECT 37.773 66.708 42.905 66.828 ;
			LAYER M4 ;
			RECT 37.773 68.724 42.905 68.844 ;
			LAYER M4 ;
			RECT 37.773 70.740 42.905 70.860 ;
			LAYER M4 ;
			RECT 37.773 72.756 42.905 72.876 ;
			LAYER M4 ;
			RECT 37.773 74.772 42.905 74.892 ;
			LAYER M4 ;
			RECT 37.773 76.788 42.905 76.908 ;
			LAYER M4 ;
			RECT 37.773 78.804 42.905 78.924 ;
			LAYER M4 ;
			RECT 37.773 80.820 42.905 80.940 ;
			LAYER M4 ;
			RECT 37.773 82.836 42.905 82.956 ;
			LAYER M4 ;
			RECT 37.773 84.852 42.905 84.972 ;
			LAYER M4 ;
			RECT 37.773 86.868 42.905 86.988 ;
			LAYER M4 ;
			RECT 37.773 88.884 42.905 89.004 ;
			LAYER M4 ;
			RECT 37.773 90.900 42.905 91.020 ;
			LAYER M4 ;
			RECT 37.773 92.916 42.905 93.036 ;
			LAYER M4 ;
			RECT 37.773 94.932 42.905 95.052 ;
			LAYER M4 ;
			RECT 37.773 96.948 42.905 97.068 ;
			LAYER M4 ;
			RECT 37.773 98.964 42.905 99.084 ;
			LAYER M4 ;
			RECT 37.773 100.980 42.905 101.100 ;
			LAYER M4 ;
			RECT 37.773 102.996 42.905 103.116 ;
		END
	END VDD

	PIN VDDM
		DIRECTION INOUT ;
		USE POWER ;
		PORT
			LAYER M4 ;
			RECT 0.120 1.428 37.623 1.548 ;
			LAYER M4 ;
			RECT 0.120 1.932 42.905 2.052 ;
			LAYER M4 ;
			RECT 0.120 2.184 42.905 2.304 ;
			LAYER M4 ;
			RECT 0.120 3.444 37.623 3.564 ;
			LAYER M4 ;
			RECT 0.120 3.948 42.905 4.068 ;
			LAYER M4 ;
			RECT 0.120 4.200 42.905 4.320 ;
			LAYER M4 ;
			RECT 0.120 5.460 37.623 5.580 ;
			LAYER M4 ;
			RECT 0.120 5.964 42.905 6.084 ;
			LAYER M4 ;
			RECT 0.120 6.216 42.905 6.336 ;
			LAYER M4 ;
			RECT 0.120 7.476 37.623 7.596 ;
			LAYER M4 ;
			RECT 0.120 7.980 42.905 8.100 ;
			LAYER M4 ;
			RECT 0.120 8.232 42.905 8.352 ;
			LAYER M4 ;
			RECT 0.120 9.492 37.623 9.612 ;
			LAYER M4 ;
			RECT 0.120 9.996 42.905 10.116 ;
			LAYER M4 ;
			RECT 0.120 10.248 42.905 10.368 ;
			LAYER M4 ;
			RECT 0.120 11.508 37.623 11.628 ;
			LAYER M4 ;
			RECT 0.120 12.012 42.905 12.132 ;
			LAYER M4 ;
			RECT 0.120 12.264 42.905 12.384 ;
			LAYER M4 ;
			RECT 0.120 13.524 37.623 13.644 ;
			LAYER M4 ;
			RECT 0.120 14.028 42.905 14.148 ;
			LAYER M4 ;
			RECT 0.120 14.280 42.905 14.400 ;
			LAYER M4 ;
			RECT 0.120 15.540 37.623 15.660 ;
			LAYER M4 ;
			RECT 0.120 16.044 42.905 16.164 ;
			LAYER M4 ;
			RECT 0.120 16.296 42.905 16.416 ;
			LAYER M4 ;
			RECT 0.120 17.556 37.623 17.676 ;
			LAYER M4 ;
			RECT 0.120 18.060 42.905 18.180 ;
			LAYER M4 ;
			RECT 0.120 18.312 42.905 18.432 ;
			LAYER M4 ;
			RECT 0.120 19.572 37.623 19.692 ;
			LAYER M4 ;
			RECT 0.120 20.076 42.905 20.196 ;
			LAYER M4 ;
			RECT 0.120 20.328 42.905 20.448 ;
			LAYER M4 ;
			RECT 0.120 21.588 37.623 21.708 ;
			LAYER M4 ;
			RECT 0.120 22.092 42.905 22.212 ;
			LAYER M4 ;
			RECT 0.120 22.344 42.905 22.464 ;
			LAYER M4 ;
			RECT 0.120 23.604 37.623 23.724 ;
			LAYER M4 ;
			RECT 0.120 24.108 42.905 24.228 ;
			LAYER M4 ;
			RECT 0.120 24.360 42.905 24.480 ;
			LAYER M4 ;
			RECT 0.120 25.620 37.623 25.740 ;
			LAYER M4 ;
			RECT 0.120 26.124 42.905 26.244 ;
			LAYER M4 ;
			RECT 0.120 26.376 42.905 26.496 ;
			LAYER M4 ;
			RECT 0.120 27.636 37.623 27.756 ;
			LAYER M4 ;
			RECT 0.120 28.140 42.905 28.260 ;
			LAYER M4 ;
			RECT 0.120 28.392 42.905 28.512 ;
			LAYER M4 ;
			RECT 0.120 29.652 37.623 29.772 ;
			LAYER M4 ;
			RECT 0.120 30.156 42.905 30.276 ;
			LAYER M4 ;
			RECT 0.120 30.408 42.905 30.528 ;
			LAYER M4 ;
			RECT 0.120 31.668 37.623 31.788 ;
			LAYER M4 ;
			RECT 0.120 32.172 42.905 32.292 ;
			LAYER M4 ;
			RECT 0.120 32.424 42.905 32.544 ;
			LAYER M4 ;
			RECT 0.120 33.684 37.623 33.804 ;
			LAYER M4 ;
			RECT 0.120 34.188 42.905 34.308 ;
			LAYER M4 ;
			RECT 0.120 34.440 42.905 34.560 ;
			LAYER M4 ;
			RECT 0.120 35.700 37.623 35.820 ;
			LAYER M4 ;
			RECT 0.120 36.204 42.905 36.324 ;
			LAYER M4 ;
			RECT 0.120 36.456 42.905 36.576 ;
			LAYER M4 ;
			RECT 0.120 37.716 37.623 37.836 ;
			LAYER M4 ;
			RECT 0.120 38.220 42.905 38.340 ;
			LAYER M4 ;
			RECT 0.120 38.472 42.905 38.592 ;
			LAYER M4 ;
			RECT 0.120 39.732 37.623 39.852 ;
			LAYER M4 ;
			RECT 0.120 40.236 42.905 40.356 ;
			LAYER M4 ;
			RECT 0.120 40.488 42.905 40.608 ;
			LAYER M4 ;
			RECT 0.120 41.748 37.623 41.868 ;
			LAYER M4 ;
			RECT 0.120 42.252 42.905 42.372 ;
			LAYER M4 ;
			RECT 0.120 42.504 42.905 42.624 ;
			LAYER M4 ;
			RECT 0.120 43.764 37.623 43.884 ;
			LAYER M4 ;
			RECT 0.120 44.268 42.905 44.388 ;
			LAYER M4 ;
			RECT 0.120 44.520 42.905 44.640 ;
			LAYER M4 ;
			RECT 0.120 45.780 37.623 45.900 ;
			LAYER M4 ;
			RECT 0.120 46.284 42.905 46.404 ;
			LAYER M4 ;
			RECT 0.120 46.536 42.905 46.656 ;
			LAYER M4 ;
			RECT 0.120 47.812 42.905 47.932 ;
			LAYER M4 ;
			RECT 0.120 48.436 37.623 48.556 ;
			LAYER M4 ;
			RECT 0.120 48.842 42.905 48.962 ;
			LAYER M4 ;
			RECT 0.120 49.302 42.905 49.422 ;
			LAYER M4 ;
			RECT 0.120 49.762 37.623 49.882 ;
			LAYER M4 ;
			RECT 0.120 50.222 42.905 50.342 ;
			LAYER M4 ;
			RECT 0.120 50.452 42.905 50.572 ;
			LAYER M4 ;
			RECT 0.120 50.844 42.905 50.964 ;
			LAYER M4 ;
			RECT 0.120 51.994 37.623 52.114 ;
			LAYER M4 ;
			RECT 0.120 52.676 42.905 52.796 ;
			LAYER M4 ;
			RECT 0.120 53.588 37.623 53.708 ;
			LAYER M4 ;
			RECT 0.120 54.767 42.905 54.887 ;
			LAYER M4 ;
			RECT 0.120 55.456 42.905 55.576 ;
			LAYER M4 ;
			RECT 0.120 55.916 42.905 56.036 ;
			LAYER M4 ;
			RECT 0.120 56.792 37.623 56.912 ;
			LAYER M4 ;
			RECT 0.120 57.252 42.905 57.372 ;
			LAYER M4 ;
			RECT 0.120 58.120 42.905 58.240 ;
			LAYER M4 ;
			RECT 0.120 58.554 42.905 58.674 ;
			LAYER M4 ;
			RECT 0.120 59.014 37.623 59.134 ;
			LAYER M4 ;
			RECT 0.120 59.424 42.905 59.544 ;
			LAYER M4 ;
			RECT 0.120 59.884 42.905 60.004 ;
			LAYER M4 ;
			RECT 0.120 60.660 37.623 60.780 ;
			LAYER M4 ;
			RECT 0.120 61.164 42.905 61.284 ;
			LAYER M4 ;
			RECT 0.120 61.416 42.905 61.536 ;
			LAYER M4 ;
			RECT 0.120 62.676 37.623 62.796 ;
			LAYER M4 ;
			RECT 0.120 63.180 42.905 63.300 ;
			LAYER M4 ;
			RECT 0.120 63.432 42.905 63.552 ;
			LAYER M4 ;
			RECT 0.120 64.692 37.623 64.812 ;
			LAYER M4 ;
			RECT 0.120 65.196 42.905 65.316 ;
			LAYER M4 ;
			RECT 0.120 65.448 42.905 65.568 ;
			LAYER M4 ;
			RECT 0.120 66.708 37.623 66.828 ;
			LAYER M4 ;
			RECT 0.120 67.212 42.905 67.332 ;
			LAYER M4 ;
			RECT 0.120 67.464 42.905 67.584 ;
			LAYER M4 ;
			RECT 0.120 68.724 37.623 68.844 ;
			LAYER M4 ;
			RECT 0.120 69.228 42.905 69.348 ;
			LAYER M4 ;
			RECT 0.120 69.480 42.905 69.600 ;
			LAYER M4 ;
			RECT 0.120 70.740 37.623 70.860 ;
			LAYER M4 ;
			RECT 0.120 71.244 42.905 71.364 ;
			LAYER M4 ;
			RECT 0.120 71.496 42.905 71.616 ;
			LAYER M4 ;
			RECT 0.120 72.756 37.623 72.876 ;
			LAYER M4 ;
			RECT 0.120 73.260 42.905 73.380 ;
			LAYER M4 ;
			RECT 0.120 73.512 42.905 73.632 ;
			LAYER M4 ;
			RECT 0.120 74.772 37.623 74.892 ;
			LAYER M4 ;
			RECT 0.120 75.276 42.905 75.396 ;
			LAYER M4 ;
			RECT 0.120 75.528 42.905 75.648 ;
			LAYER M4 ;
			RECT 0.120 76.788 37.623 76.908 ;
			LAYER M4 ;
			RECT 0.120 77.292 42.905 77.412 ;
			LAYER M4 ;
			RECT 0.120 77.544 42.905 77.664 ;
			LAYER M4 ;
			RECT 0.120 78.804 37.623 78.924 ;
			LAYER M4 ;
			RECT 0.120 79.308 42.905 79.428 ;
			LAYER M4 ;
			RECT 0.120 79.560 42.905 79.680 ;
			LAYER M4 ;
			RECT 0.120 80.820 37.623 80.940 ;
			LAYER M4 ;
			RECT 0.120 81.324 42.905 81.444 ;
			LAYER M4 ;
			RECT 0.120 81.576 42.905 81.696 ;
			LAYER M4 ;
			RECT 0.120 82.836 37.623 82.956 ;
			LAYER M4 ;
			RECT 0.120 83.340 42.905 83.460 ;
			LAYER M4 ;
			RECT 0.120 83.592 42.905 83.712 ;
			LAYER M4 ;
			RECT 0.120 84.852 37.623 84.972 ;
			LAYER M4 ;
			RECT 0.120 85.356 42.905 85.476 ;
			LAYER M4 ;
			RECT 0.120 85.608 42.905 85.728 ;
			LAYER M4 ;
			RECT 0.120 86.868 37.623 86.988 ;
			LAYER M4 ;
			RECT 0.120 87.372 42.905 87.492 ;
			LAYER M4 ;
			RECT 0.120 87.624 42.905 87.744 ;
			LAYER M4 ;
			RECT 0.120 88.884 37.623 89.004 ;
			LAYER M4 ;
			RECT 0.120 89.388 42.905 89.508 ;
			LAYER M4 ;
			RECT 0.120 89.640 42.905 89.760 ;
			LAYER M4 ;
			RECT 0.120 90.900 37.623 91.020 ;
			LAYER M4 ;
			RECT 0.120 91.404 42.905 91.524 ;
			LAYER M4 ;
			RECT 0.120 91.656 42.905 91.776 ;
			LAYER M4 ;
			RECT 0.120 92.916 37.623 93.036 ;
			LAYER M4 ;
			RECT 0.120 93.420 42.905 93.540 ;
			LAYER M4 ;
			RECT 0.120 93.672 42.905 93.792 ;
			LAYER M4 ;
			RECT 0.120 94.932 37.623 95.052 ;
			LAYER M4 ;
			RECT 0.120 95.436 42.905 95.556 ;
			LAYER M4 ;
			RECT 0.120 95.688 42.905 95.808 ;
			LAYER M4 ;
			RECT 0.120 96.948 37.623 97.068 ;
			LAYER M4 ;
			RECT 0.120 97.452 42.905 97.572 ;
			LAYER M4 ;
			RECT 0.120 97.704 42.905 97.824 ;
			LAYER M4 ;
			RECT 0.120 98.964 37.623 99.084 ;
			LAYER M4 ;
			RECT 0.120 99.468 42.905 99.588 ;
			LAYER M4 ;
			RECT 0.120 99.720 42.905 99.840 ;
			LAYER M4 ;
			RECT 0.120 100.980 37.623 101.100 ;
			LAYER M4 ;
			RECT 0.120 101.484 42.905 101.604 ;
			LAYER M4 ;
			RECT 0.120 101.736 42.905 101.856 ;
			LAYER M4 ;
			RECT 0.120 102.996 37.623 103.116 ;
			LAYER M4 ;
			RECT 0.120 103.500 42.905 103.620 ;
			LAYER M4 ;
			RECT 0.120 103.752 42.905 103.872 ;
		END
	END VDDM

	PIN VSS
		DIRECTION INOUT ;
		USE GROUND ;
		PORT
			LAYER M4 ;
			RECT 0.120 1.176 42.905 1.296 ;
			LAYER M4 ;
			RECT 0.120 1.680 42.905 1.800 ;
			LAYER M4 ;
			RECT 0.120 2.688 42.905 2.808 ;
			LAYER M4 ;
			RECT 0.120 3.192 42.905 3.312 ;
			LAYER M4 ;
			RECT 0.120 3.696 42.905 3.816 ;
			LAYER M4 ;
			RECT 0.120 4.704 42.905 4.824 ;
			LAYER M4 ;
			RECT 0.120 5.208 42.905 5.328 ;
			LAYER M4 ;
			RECT 0.120 5.712 42.905 5.832 ;
			LAYER M4 ;
			RECT 0.120 6.720 42.905 6.840 ;
			LAYER M4 ;
			RECT 0.120 7.224 42.905 7.344 ;
			LAYER M4 ;
			RECT 0.120 7.728 42.905 7.848 ;
			LAYER M4 ;
			RECT 0.120 8.736 42.905 8.856 ;
			LAYER M4 ;
			RECT 0.120 9.240 42.905 9.360 ;
			LAYER M4 ;
			RECT 0.120 9.744 42.905 9.864 ;
			LAYER M4 ;
			RECT 0.120 10.752 42.905 10.872 ;
			LAYER M4 ;
			RECT 0.120 11.256 42.905 11.376 ;
			LAYER M4 ;
			RECT 0.120 11.760 42.905 11.880 ;
			LAYER M4 ;
			RECT 0.120 12.768 42.905 12.888 ;
			LAYER M4 ;
			RECT 0.120 13.272 42.905 13.392 ;
			LAYER M4 ;
			RECT 0.120 13.776 42.905 13.896 ;
			LAYER M4 ;
			RECT 0.120 14.784 42.905 14.904 ;
			LAYER M4 ;
			RECT 0.120 15.288 42.905 15.408 ;
			LAYER M4 ;
			RECT 0.120 15.792 42.905 15.912 ;
			LAYER M4 ;
			RECT 0.120 16.800 42.905 16.920 ;
			LAYER M4 ;
			RECT 0.120 17.304 42.905 17.424 ;
			LAYER M4 ;
			RECT 0.120 17.808 42.905 17.928 ;
			LAYER M4 ;
			RECT 0.120 18.816 42.905 18.936 ;
			LAYER M4 ;
			RECT 0.120 19.320 42.905 19.440 ;
			LAYER M4 ;
			RECT 0.120 19.824 42.905 19.944 ;
			LAYER M4 ;
			RECT 0.120 20.832 42.905 20.952 ;
			LAYER M4 ;
			RECT 0.120 21.336 42.905 21.456 ;
			LAYER M4 ;
			RECT 0.120 21.840 42.905 21.960 ;
			LAYER M4 ;
			RECT 0.120 22.848 42.905 22.968 ;
			LAYER M4 ;
			RECT 0.120 23.352 42.905 23.472 ;
			LAYER M4 ;
			RECT 0.120 23.856 42.905 23.976 ;
			LAYER M4 ;
			RECT 0.120 24.864 42.905 24.984 ;
			LAYER M4 ;
			RECT 0.120 25.368 42.905 25.488 ;
			LAYER M4 ;
			RECT 0.120 25.872 42.905 25.992 ;
			LAYER M4 ;
			RECT 0.120 26.880 42.905 27.000 ;
			LAYER M4 ;
			RECT 0.120 27.384 42.905 27.504 ;
			LAYER M4 ;
			RECT 0.120 27.888 42.905 28.008 ;
			LAYER M4 ;
			RECT 0.120 28.896 42.905 29.016 ;
			LAYER M4 ;
			RECT 0.120 29.400 42.905 29.520 ;
			LAYER M4 ;
			RECT 0.120 29.904 42.905 30.024 ;
			LAYER M4 ;
			RECT 0.120 30.912 42.905 31.032 ;
			LAYER M4 ;
			RECT 0.120 31.416 42.905 31.536 ;
			LAYER M4 ;
			RECT 0.120 31.920 42.905 32.040 ;
			LAYER M4 ;
			RECT 0.120 32.928 42.905 33.048 ;
			LAYER M4 ;
			RECT 0.120 33.432 42.905 33.552 ;
			LAYER M4 ;
			RECT 0.120 33.936 42.905 34.056 ;
			LAYER M4 ;
			RECT 0.120 34.944 42.905 35.064 ;
			LAYER M4 ;
			RECT 0.120 35.448 42.905 35.568 ;
			LAYER M4 ;
			RECT 0.120 35.952 42.905 36.072 ;
			LAYER M4 ;
			RECT 0.120 36.960 42.905 37.080 ;
			LAYER M4 ;
			RECT 0.120 37.464 42.905 37.584 ;
			LAYER M4 ;
			RECT 0.120 37.968 42.905 38.088 ;
			LAYER M4 ;
			RECT 0.120 38.976 42.905 39.096 ;
			LAYER M4 ;
			RECT 0.120 39.480 42.905 39.600 ;
			LAYER M4 ;
			RECT 0.120 39.984 42.905 40.104 ;
			LAYER M4 ;
			RECT 0.120 40.992 42.905 41.112 ;
			LAYER M4 ;
			RECT 0.120 41.496 42.905 41.616 ;
			LAYER M4 ;
			RECT 0.120 42.000 42.905 42.120 ;
			LAYER M4 ;
			RECT 0.120 43.008 42.905 43.128 ;
			LAYER M4 ;
			RECT 0.120 43.512 42.905 43.632 ;
			LAYER M4 ;
			RECT 0.120 44.016 42.905 44.136 ;
			LAYER M4 ;
			RECT 0.120 45.024 42.905 45.144 ;
			LAYER M4 ;
			RECT 0.120 45.528 42.905 45.648 ;
			LAYER M4 ;
			RECT 0.120 46.032 42.905 46.152 ;
			LAYER M4 ;
			RECT 0.120 47.040 42.905 47.160 ;
			LAYER M4 ;
			RECT 0.120 48.206 42.905 48.326 ;
			LAYER M4 ;
			RECT 0.120 49.072 42.905 49.192 ;
			LAYER M4 ;
			RECT 0.120 49.532 42.905 49.652 ;
			LAYER M4 ;
			RECT 0.120 49.992 42.905 50.112 ;
			LAYER M4 ;
			RECT 0.120 51.074 42.905 51.194 ;
			LAYER M4 ;
			RECT 0.120 51.764 42.905 51.884 ;
			LAYER M4 ;
			RECT 0.120 52.906 42.905 53.026 ;
			LAYER M4 ;
			RECT 0.120 53.818 42.905 53.938 ;
			LAYER M4 ;
			RECT 0.120 54.537 42.905 54.657 ;
			LAYER M4 ;
			RECT 0.120 55.686 42.905 55.806 ;
			LAYER M4 ;
			RECT 0.120 56.146 42.905 56.266 ;
			LAYER M4 ;
			RECT 0.120 56.562 42.905 56.682 ;
			LAYER M4 ;
			RECT 0.120 57.022 42.905 57.142 ;
			LAYER M4 ;
			RECT 0.120 57.482 42.905 57.602 ;
			LAYER M4 ;
			RECT 0.120 57.890 42.905 58.010 ;
			LAYER M4 ;
			RECT 0.120 58.784 42.905 58.904 ;
			LAYER M4 ;
			RECT 0.120 59.654 42.905 59.774 ;
			LAYER M4 ;
			RECT 0.120 60.408 42.905 60.528 ;
			LAYER M4 ;
			RECT 0.120 60.912 42.905 61.032 ;
			LAYER M4 ;
			RECT 0.120 61.920 42.905 62.040 ;
			LAYER M4 ;
			RECT 0.120 62.424 42.905 62.544 ;
			LAYER M4 ;
			RECT 0.120 62.928 42.905 63.048 ;
			LAYER M4 ;
			RECT 0.120 63.936 42.905 64.056 ;
			LAYER M4 ;
			RECT 0.120 64.440 42.905 64.560 ;
			LAYER M4 ;
			RECT 0.120 64.944 42.905 65.064 ;
			LAYER M4 ;
			RECT 0.120 65.952 42.905 66.072 ;
			LAYER M4 ;
			RECT 0.120 66.456 42.905 66.576 ;
			LAYER M4 ;
			RECT 0.120 66.960 42.905 67.080 ;
			LAYER M4 ;
			RECT 0.120 67.968 42.905 68.088 ;
			LAYER M4 ;
			RECT 0.120 68.472 42.905 68.592 ;
			LAYER M4 ;
			RECT 0.120 68.976 42.905 69.096 ;
			LAYER M4 ;
			RECT 0.120 69.984 42.905 70.104 ;
			LAYER M4 ;
			RECT 0.120 70.488 42.905 70.608 ;
			LAYER M4 ;
			RECT 0.120 70.992 42.905 71.112 ;
			LAYER M4 ;
			RECT 0.120 72.000 42.905 72.120 ;
			LAYER M4 ;
			RECT 0.120 72.504 42.905 72.624 ;
			LAYER M4 ;
			RECT 0.120 73.008 42.905 73.128 ;
			LAYER M4 ;
			RECT 0.120 74.016 42.905 74.136 ;
			LAYER M4 ;
			RECT 0.120 74.520 42.905 74.640 ;
			LAYER M4 ;
			RECT 0.120 75.024 42.905 75.144 ;
			LAYER M4 ;
			RECT 0.120 76.032 42.905 76.152 ;
			LAYER M4 ;
			RECT 0.120 76.536 42.905 76.656 ;
			LAYER M4 ;
			RECT 0.120 77.040 42.905 77.160 ;
			LAYER M4 ;
			RECT 0.120 78.048 42.905 78.168 ;
			LAYER M4 ;
			RECT 0.120 78.552 42.905 78.672 ;
			LAYER M4 ;
			RECT 0.120 79.056 42.905 79.176 ;
			LAYER M4 ;
			RECT 0.120 80.064 42.905 80.184 ;
			LAYER M4 ;
			RECT 0.120 80.568 42.905 80.688 ;
			LAYER M4 ;
			RECT 0.120 81.072 42.905 81.192 ;
			LAYER M4 ;
			RECT 0.120 82.080 42.905 82.200 ;
			LAYER M4 ;
			RECT 0.120 82.584 42.905 82.704 ;
			LAYER M4 ;
			RECT 0.120 83.088 42.905 83.208 ;
			LAYER M4 ;
			RECT 0.120 84.096 42.905 84.216 ;
			LAYER M4 ;
			RECT 0.120 84.600 42.905 84.720 ;
			LAYER M4 ;
			RECT 0.120 85.104 42.905 85.224 ;
			LAYER M4 ;
			RECT 0.120 86.112 42.905 86.232 ;
			LAYER M4 ;
			RECT 0.120 86.616 42.905 86.736 ;
			LAYER M4 ;
			RECT 0.120 87.120 42.905 87.240 ;
			LAYER M4 ;
			RECT 0.120 88.128 42.905 88.248 ;
			LAYER M4 ;
			RECT 0.120 88.632 42.905 88.752 ;
			LAYER M4 ;
			RECT 0.120 89.136 42.905 89.256 ;
			LAYER M4 ;
			RECT 0.120 90.144 42.905 90.264 ;
			LAYER M4 ;
			RECT 0.120 90.648 42.905 90.768 ;
			LAYER M4 ;
			RECT 0.120 91.152 42.905 91.272 ;
			LAYER M4 ;
			RECT 0.120 92.160 42.905 92.280 ;
			LAYER M4 ;
			RECT 0.120 92.664 42.905 92.784 ;
			LAYER M4 ;
			RECT 0.120 93.168 42.905 93.288 ;
			LAYER M4 ;
			RECT 0.120 94.176 42.905 94.296 ;
			LAYER M4 ;
			RECT 0.120 94.680 42.905 94.800 ;
			LAYER M4 ;
			RECT 0.120 95.184 42.905 95.304 ;
			LAYER M4 ;
			RECT 0.120 96.192 42.905 96.312 ;
			LAYER M4 ;
			RECT 0.120 96.696 42.905 96.816 ;
			LAYER M4 ;
			RECT 0.120 97.200 42.905 97.320 ;
			LAYER M4 ;
			RECT 0.120 98.208 42.905 98.328 ;
			LAYER M4 ;
			RECT 0.120 98.712 42.905 98.832 ;
			LAYER M4 ;
			RECT 0.120 99.216 42.905 99.336 ;
			LAYER M4 ;
			RECT 0.120 100.224 42.905 100.344 ;
			LAYER M4 ;
			RECT 0.120 100.728 42.905 100.848 ;
			LAYER M4 ;
			RECT 0.120 101.232 42.905 101.352 ;
			LAYER M4 ;
			RECT 0.120 102.240 42.905 102.360 ;
			LAYER M4 ;
			RECT 0.120 102.744 42.905 102.864 ;
			LAYER M4 ;
			RECT 0.120 103.248 42.905 103.368 ;
			LAYER M4 ;
			RECT 0.120 104.256 42.905 104.376 ;
		END
	END VSS

	PIN WEB
		DIRECTION INPUT ;
		USE SIGNAL ;
		PORT
			LAYER M1 ;
			RECT 42.777 51.944 43.025 52.024 ;
			LAYER M2 ;
			RECT 42.777 51.944 43.025 52.024 ;
			LAYER M3 ;
			RECT 42.777 51.944 43.025 52.024 ;
		END
	END WEB

	PIN WTSEL[0]
		DIRECTION INPUT ;
		USE SIGNAL ;
		PORT
			LAYER M1 ;
			RECT 42.777 51.752 43.025 51.832 ;
			LAYER M2 ;
			RECT 42.777 51.752 43.025 51.832 ;
			LAYER M3 ;
			RECT 42.777 51.752 43.025 51.832 ;
		END
	END WTSEL[0]

	PIN WTSEL[1]
		DIRECTION INPUT ;
		USE SIGNAL ;
		PORT
			LAYER M1 ;
			RECT 42.777 52.904 43.025 52.984 ;
			LAYER M2 ;
			RECT 42.777 52.904 43.025 52.984 ;
			LAYER M3 ;
			RECT 42.777 52.904 43.025 52.984 ;
		END
	END WTSEL[1]

	OBS
		LAYER M1 ;
		RECT 0.000 0.000 43.025 105.552 ;
		LAYER M2 ;
		RECT 0.000 0.000 43.025 105.552 ;
		LAYER M3 ;
		RECT 0.000 0.000 43.025 105.552 ;
		LAYER M4 ;
		RECT 0.283 105.001 42.625 105.121 ;
		LAYER M4 ;
		RECT 0.300 0.431 42.625 0.551 ;
		LAYER M4 ;
		RECT 0.723 59.224 38.073 59.301 ;
		LAYER M4 ;
		RECT 1.218 52.181 38.073 52.279 ;
		LAYER M4 ;
		RECT 1.218 52.361 38.073 52.459 ;
		LAYER M4 ;
		RECT 1.218 52.541 38.073 52.639 ;
		LAYER M4 ;
		RECT 1.218 53.093 38.073 53.191 ;
		LAYER M4 ;
		RECT 1.218 53.273 38.073 53.371 ;
		LAYER M4 ;
		RECT 1.218 53.453 38.073 53.551 ;
		LAYER M4 ;
		RECT 1.218 54.039 38.073 54.137 ;
		LAYER M4 ;
		RECT 1.218 54.219 38.073 54.317 ;
		LAYER M4 ;
		RECT 1.218 54.399 38.073 54.497 ;
		LAYER M4 ;
		RECT 1.218 54.951 38.073 55.049 ;
		LAYER M4 ;
		RECT 1.218 55.131 38.073 55.229 ;
		LAYER M4 ;
		RECT 1.218 55.311 38.073 55.409 ;
		LAYER M4 ;
		RECT 1.668 51.229 38.073 51.327 ;
		LAYER M4 ;
		RECT 1.668 51.409 38.073 51.507 ;
		LAYER M4 ;
		RECT 1.668 51.589 38.073 51.687 ;
		LAYER M4 ;
		RECT 30.067 1.330 31.069 1.394 ;
		LAYER M4 ;
		RECT 30.067 2.590 31.069 2.654 ;
		LAYER M4 ;
		RECT 30.067 3.346 31.069 3.410 ;
		LAYER M4 ;
		RECT 30.067 4.606 31.069 4.670 ;
		LAYER M4 ;
		RECT 30.067 5.362 31.069 5.426 ;
		LAYER M4 ;
		RECT 30.067 6.622 31.069 6.686 ;
		LAYER M4 ;
		RECT 30.067 7.378 31.069 7.442 ;
		LAYER M4 ;
		RECT 30.067 8.638 31.069 8.702 ;
		LAYER M4 ;
		RECT 30.067 9.394 31.069 9.458 ;
		LAYER M4 ;
		RECT 30.067 10.654 31.069 10.718 ;
		LAYER M4 ;
		RECT 30.067 11.410 31.069 11.474 ;
		LAYER M4 ;
		RECT 30.067 12.670 31.069 12.734 ;
		LAYER M4 ;
		RECT 30.067 13.426 31.069 13.490 ;
		LAYER M4 ;
		RECT 30.067 14.686 31.069 14.750 ;
		LAYER M4 ;
		RECT 30.067 15.442 31.069 15.506 ;
		LAYER M4 ;
		RECT 30.067 16.702 31.069 16.766 ;
		LAYER M4 ;
		RECT 30.067 17.458 31.069 17.522 ;
		LAYER M4 ;
		RECT 30.067 18.718 31.069 18.782 ;
		LAYER M4 ;
		RECT 30.067 19.474 31.069 19.538 ;
		LAYER M4 ;
		RECT 30.067 20.734 31.069 20.798 ;
		LAYER M4 ;
		RECT 30.067 21.490 31.069 21.554 ;
		LAYER M4 ;
		RECT 30.067 22.750 31.069 22.814 ;
		LAYER M4 ;
		RECT 30.067 23.506 31.069 23.570 ;
		LAYER M4 ;
		RECT 30.067 24.766 31.069 24.830 ;
		LAYER M4 ;
		RECT 30.067 25.522 31.069 25.586 ;
		LAYER M4 ;
		RECT 30.067 26.782 31.069 26.846 ;
		LAYER M4 ;
		RECT 30.067 27.538 31.069 27.602 ;
		LAYER M4 ;
		RECT 30.067 28.798 31.069 28.862 ;
		LAYER M4 ;
		RECT 30.067 29.554 31.069 29.618 ;
		LAYER M4 ;
		RECT 30.067 30.814 31.069 30.878 ;
		LAYER M4 ;
		RECT 30.067 31.570 31.069 31.634 ;
		LAYER M4 ;
		RECT 30.067 32.830 31.069 32.894 ;
		LAYER M4 ;
		RECT 30.067 33.586 31.069 33.650 ;
		LAYER M4 ;
		RECT 30.067 34.846 31.069 34.910 ;
		LAYER M4 ;
		RECT 30.067 35.602 31.069 35.666 ;
		LAYER M4 ;
		RECT 30.067 36.862 31.069 36.926 ;
		LAYER M4 ;
		RECT 30.067 37.618 31.069 37.682 ;
		LAYER M4 ;
		RECT 30.067 38.878 31.069 38.942 ;
		LAYER M4 ;
		RECT 30.067 39.634 31.069 39.698 ;
		LAYER M4 ;
		RECT 30.067 40.894 31.069 40.958 ;
		LAYER M4 ;
		RECT 30.067 41.650 31.069 41.714 ;
		LAYER M4 ;
		RECT 30.067 42.910 31.069 42.974 ;
		LAYER M4 ;
		RECT 30.067 43.666 31.069 43.730 ;
		LAYER M4 ;
		RECT 30.067 44.926 31.069 44.990 ;
		LAYER M4 ;
		RECT 30.067 45.682 31.069 45.746 ;
		LAYER M4 ;
		RECT 30.067 46.942 31.069 47.006 ;
		LAYER M4 ;
		RECT 30.067 60.562 31.069 60.626 ;
		LAYER M4 ;
		RECT 30.067 61.822 31.069 61.886 ;
		LAYER M4 ;
		RECT 30.067 62.578 31.069 62.642 ;
		LAYER M4 ;
		RECT 30.067 63.838 31.069 63.902 ;
		LAYER M4 ;
		RECT 30.067 64.594 31.069 64.658 ;
		LAYER M4 ;
		RECT 30.067 65.854 31.069 65.918 ;
		LAYER M4 ;
		RECT 30.067 66.610 31.069 66.674 ;
		LAYER M4 ;
		RECT 30.067 67.870 31.069 67.934 ;
		LAYER M4 ;
		RECT 30.067 68.626 31.069 68.690 ;
		LAYER M4 ;
		RECT 30.067 69.886 31.069 69.950 ;
		LAYER M4 ;
		RECT 30.067 70.642 31.069 70.706 ;
		LAYER M4 ;
		RECT 30.067 71.902 31.069 71.966 ;
		LAYER M4 ;
		RECT 30.067 72.658 31.069 72.722 ;
		LAYER M4 ;
		RECT 30.067 73.918 31.069 73.982 ;
		LAYER M4 ;
		RECT 30.067 74.674 31.069 74.738 ;
		LAYER M4 ;
		RECT 30.067 75.934 31.069 75.998 ;
		LAYER M4 ;
		RECT 30.067 76.690 31.069 76.754 ;
		LAYER M4 ;
		RECT 30.067 77.950 31.069 78.014 ;
		LAYER M4 ;
		RECT 30.067 78.706 31.069 78.770 ;
		LAYER M4 ;
		RECT 30.067 79.966 31.069 80.030 ;
		LAYER M4 ;
		RECT 30.067 80.722 31.069 80.786 ;
		LAYER M4 ;
		RECT 30.067 81.982 31.069 82.046 ;
		LAYER M4 ;
		RECT 30.067 82.738 31.069 82.802 ;
		LAYER M4 ;
		RECT 30.067 83.998 31.069 84.062 ;
		LAYER M4 ;
		RECT 30.067 84.754 31.069 84.818 ;
		LAYER M4 ;
		RECT 30.067 86.014 31.069 86.078 ;
		LAYER M4 ;
		RECT 30.067 86.770 31.069 86.834 ;
		LAYER M4 ;
		RECT 30.067 88.030 31.069 88.094 ;
		LAYER M4 ;
		RECT 30.067 88.786 31.069 88.850 ;
		LAYER M4 ;
		RECT 30.067 90.046 31.069 90.110 ;
		LAYER M4 ;
		RECT 30.067 90.802 31.069 90.866 ;
		LAYER M4 ;
		RECT 30.067 92.062 31.069 92.126 ;
		LAYER M4 ;
		RECT 30.067 92.818 31.069 92.882 ;
		LAYER M4 ;
		RECT 30.067 94.078 31.069 94.142 ;
		LAYER M4 ;
		RECT 30.067 94.834 31.069 94.898 ;
		LAYER M4 ;
		RECT 30.067 96.094 31.069 96.158 ;
		LAYER M4 ;
		RECT 30.067 96.850 31.069 96.914 ;
		LAYER M4 ;
		RECT 30.067 98.110 31.069 98.174 ;
		LAYER M4 ;
		RECT 30.067 98.866 31.069 98.930 ;
		LAYER M4 ;
		RECT 30.067 100.126 31.069 100.190 ;
		LAYER M4 ;
		RECT 30.067 100.882 31.069 100.946 ;
		LAYER M4 ;
		RECT 30.067 102.142 31.069 102.206 ;
		LAYER M4 ;
		RECT 30.067 102.898 31.069 102.962 ;
		LAYER M4 ;
		RECT 30.067 104.158 31.069 104.222 ;
		LAYER M4 ;
		RECT 31.861 1.337 33.839 1.387 ;
		LAYER M4 ;
		RECT 31.861 2.597 33.839 2.647 ;
		LAYER M4 ;
		RECT 31.861 3.353 33.839 3.403 ;
		LAYER M4 ;
		RECT 31.861 4.613 33.839 4.663 ;
		LAYER M4 ;
		RECT 31.861 5.369 33.839 5.419 ;
		LAYER M4 ;
		RECT 31.861 6.629 33.839 6.679 ;
		LAYER M4 ;
		RECT 31.861 7.385 33.839 7.435 ;
		LAYER M4 ;
		RECT 31.861 8.645 33.839 8.695 ;
		LAYER M4 ;
		RECT 31.861 9.401 33.839 9.451 ;
		LAYER M4 ;
		RECT 31.861 10.661 33.839 10.711 ;
		LAYER M4 ;
		RECT 31.861 11.417 33.839 11.467 ;
		LAYER M4 ;
		RECT 31.861 12.677 33.839 12.727 ;
		LAYER M4 ;
		RECT 31.861 13.433 33.839 13.483 ;
		LAYER M4 ;
		RECT 31.861 14.693 33.839 14.743 ;
		LAYER M4 ;
		RECT 31.861 15.449 33.839 15.499 ;
		LAYER M4 ;
		RECT 31.861 16.709 33.839 16.759 ;
		LAYER M4 ;
		RECT 31.861 17.465 33.839 17.515 ;
		LAYER M4 ;
		RECT 31.861 18.725 33.839 18.775 ;
		LAYER M4 ;
		RECT 31.861 19.481 33.839 19.531 ;
		LAYER M4 ;
		RECT 31.861 20.741 33.839 20.791 ;
		LAYER M4 ;
		RECT 31.861 21.497 33.839 21.547 ;
		LAYER M4 ;
		RECT 31.861 22.757 33.839 22.807 ;
		LAYER M4 ;
		RECT 31.861 23.513 33.839 23.563 ;
		LAYER M4 ;
		RECT 31.861 24.773 33.839 24.823 ;
		LAYER M4 ;
		RECT 31.861 25.529 33.839 25.579 ;
		LAYER M4 ;
		RECT 31.861 26.789 33.839 26.839 ;
		LAYER M4 ;
		RECT 31.861 27.545 33.839 27.595 ;
		LAYER M4 ;
		RECT 31.861 28.805 33.839 28.855 ;
		LAYER M4 ;
		RECT 31.861 29.561 33.839 29.611 ;
		LAYER M4 ;
		RECT 31.861 30.821 33.839 30.871 ;
		LAYER M4 ;
		RECT 31.861 31.577 33.839 31.627 ;
		LAYER M4 ;
		RECT 31.861 32.837 33.839 32.887 ;
		LAYER M4 ;
		RECT 31.861 33.593 33.839 33.643 ;
		LAYER M4 ;
		RECT 31.861 34.853 33.839 34.903 ;
		LAYER M4 ;
		RECT 31.861 35.609 33.839 35.659 ;
		LAYER M4 ;
		RECT 31.861 36.869 33.839 36.919 ;
		LAYER M4 ;
		RECT 31.861 37.625 33.839 37.675 ;
		LAYER M4 ;
		RECT 31.861 38.885 33.839 38.935 ;
		LAYER M4 ;
		RECT 31.861 39.641 33.839 39.691 ;
		LAYER M4 ;
		RECT 31.861 40.901 33.839 40.951 ;
		LAYER M4 ;
		RECT 31.861 41.657 33.839 41.707 ;
		LAYER M4 ;
		RECT 31.861 42.917 33.839 42.967 ;
		LAYER M4 ;
		RECT 31.861 43.673 33.839 43.723 ;
		LAYER M4 ;
		RECT 31.861 44.933 33.839 44.983 ;
		LAYER M4 ;
		RECT 31.861 45.689 33.839 45.739 ;
		LAYER M4 ;
		RECT 31.861 46.949 33.839 46.999 ;
		LAYER M4 ;
		RECT 31.861 60.569 33.839 60.619 ;
		LAYER M4 ;
		RECT 31.861 61.829 33.839 61.879 ;
		LAYER M4 ;
		RECT 31.861 62.585 33.839 62.635 ;
		LAYER M4 ;
		RECT 31.861 63.845 33.839 63.895 ;
		LAYER M4 ;
		RECT 31.861 64.601 33.839 64.651 ;
		LAYER M4 ;
		RECT 31.861 65.861 33.839 65.911 ;
		LAYER M4 ;
		RECT 31.861 66.617 33.839 66.667 ;
		LAYER M4 ;
		RECT 31.861 67.877 33.839 67.927 ;
		LAYER M4 ;
		RECT 31.861 68.633 33.839 68.683 ;
		LAYER M4 ;
		RECT 31.861 69.893 33.839 69.943 ;
		LAYER M4 ;
		RECT 31.861 70.649 33.839 70.699 ;
		LAYER M4 ;
		RECT 31.861 71.909 33.839 71.959 ;
		LAYER M4 ;
		RECT 31.861 72.665 33.839 72.715 ;
		LAYER M4 ;
		RECT 31.861 73.925 33.839 73.975 ;
		LAYER M4 ;
		RECT 31.861 74.681 33.839 74.731 ;
		LAYER M4 ;
		RECT 31.861 75.941 33.839 75.991 ;
		LAYER M4 ;
		RECT 31.861 76.697 33.839 76.747 ;
		LAYER M4 ;
		RECT 31.861 77.957 33.839 78.007 ;
		LAYER M4 ;
		RECT 31.861 78.713 33.839 78.763 ;
		LAYER M4 ;
		RECT 31.861 79.973 33.839 80.023 ;
		LAYER M4 ;
		RECT 31.861 80.729 33.839 80.779 ;
		LAYER M4 ;
		RECT 31.861 81.989 33.839 82.039 ;
		LAYER M4 ;
		RECT 31.861 82.745 33.839 82.795 ;
		LAYER M4 ;
		RECT 31.861 84.005 33.839 84.055 ;
		LAYER M4 ;
		RECT 31.861 84.761 33.839 84.811 ;
		LAYER M4 ;
		RECT 31.861 86.021 33.839 86.071 ;
		LAYER M4 ;
		RECT 31.861 86.777 33.839 86.827 ;
		LAYER M4 ;
		RECT 31.861 88.037 33.839 88.087 ;
		LAYER M4 ;
		RECT 31.861 88.793 33.839 88.843 ;
		LAYER M4 ;
		RECT 31.861 90.053 33.839 90.103 ;
		LAYER M4 ;
		RECT 31.861 90.809 33.839 90.859 ;
		LAYER M4 ;
		RECT 31.861 92.069 33.839 92.119 ;
		LAYER M4 ;
		RECT 31.861 92.825 33.839 92.875 ;
		LAYER M4 ;
		RECT 31.861 94.085 33.839 94.135 ;
		LAYER M4 ;
		RECT 31.861 94.841 33.839 94.891 ;
		LAYER M4 ;
		RECT 31.861 96.101 33.839 96.151 ;
		LAYER M4 ;
		RECT 31.861 96.857 33.839 96.907 ;
		LAYER M4 ;
		RECT 31.861 98.117 33.839 98.167 ;
		LAYER M4 ;
		RECT 31.861 98.873 33.839 98.923 ;
		LAYER M4 ;
		RECT 31.861 100.133 33.839 100.183 ;
		LAYER M4 ;
		RECT 31.861 100.889 33.839 100.939 ;
		LAYER M4 ;
		RECT 31.861 102.149 33.839 102.199 ;
		LAYER M4 ;
		RECT 31.861 102.905 33.839 102.955 ;
		LAYER M4 ;
		RECT 31.861 104.165 33.839 104.215 ;
		LAYER M4 ;
		RECT 33.037 1.589 33.929 1.639 ;
		LAYER M4 ;
		RECT 33.037 2.343 33.929 2.393 ;
		LAYER M4 ;
		RECT 33.037 3.605 33.929 3.655 ;
		LAYER M4 ;
		RECT 33.037 4.359 33.929 4.409 ;
		LAYER M4 ;
		RECT 33.037 5.621 33.929 5.671 ;
		LAYER M4 ;
		RECT 33.037 6.375 33.929 6.425 ;
		LAYER M4 ;
		RECT 33.037 7.637 33.929 7.687 ;
		LAYER M4 ;
		RECT 33.037 8.391 33.929 8.441 ;
		LAYER M4 ;
		RECT 33.037 9.653 33.929 9.703 ;
		LAYER M4 ;
		RECT 33.037 10.407 33.929 10.457 ;
		LAYER M4 ;
		RECT 33.037 11.669 33.929 11.719 ;
		LAYER M4 ;
		RECT 33.037 12.423 33.929 12.473 ;
		LAYER M4 ;
		RECT 33.037 13.685 33.929 13.735 ;
		LAYER M4 ;
		RECT 33.037 14.439 33.929 14.489 ;
		LAYER M4 ;
		RECT 33.037 15.701 33.929 15.751 ;
		LAYER M4 ;
		RECT 33.037 16.455 33.929 16.505 ;
		LAYER M4 ;
		RECT 33.037 17.717 33.929 17.767 ;
		LAYER M4 ;
		RECT 33.037 18.471 33.929 18.521 ;
		LAYER M4 ;
		RECT 33.037 19.733 33.929 19.783 ;
		LAYER M4 ;
		RECT 33.037 20.487 33.929 20.537 ;
		LAYER M4 ;
		RECT 33.037 21.749 33.929 21.799 ;
		LAYER M4 ;
		RECT 33.037 22.503 33.929 22.553 ;
		LAYER M4 ;
		RECT 33.037 23.765 33.929 23.815 ;
		LAYER M4 ;
		RECT 33.037 24.519 33.929 24.569 ;
		LAYER M4 ;
		RECT 33.037 25.781 33.929 25.831 ;
		LAYER M4 ;
		RECT 33.037 26.535 33.929 26.585 ;
		LAYER M4 ;
		RECT 33.037 27.797 33.929 27.847 ;
		LAYER M4 ;
		RECT 33.037 28.551 33.929 28.601 ;
		LAYER M4 ;
		RECT 33.037 29.813 33.929 29.863 ;
		LAYER M4 ;
		RECT 33.037 30.567 33.929 30.617 ;
		LAYER M4 ;
		RECT 33.037 31.829 33.929 31.879 ;
		LAYER M4 ;
		RECT 33.037 32.583 33.929 32.633 ;
		LAYER M4 ;
		RECT 33.037 33.845 33.929 33.895 ;
		LAYER M4 ;
		RECT 33.037 34.599 33.929 34.649 ;
		LAYER M4 ;
		RECT 33.037 35.861 33.929 35.911 ;
		LAYER M4 ;
		RECT 33.037 36.615 33.929 36.665 ;
		LAYER M4 ;
		RECT 33.037 37.877 33.929 37.927 ;
		LAYER M4 ;
		RECT 33.037 38.631 33.929 38.681 ;
		LAYER M4 ;
		RECT 33.037 39.893 33.929 39.943 ;
		LAYER M4 ;
		RECT 33.037 40.647 33.929 40.697 ;
		LAYER M4 ;
		RECT 33.037 41.909 33.929 41.959 ;
		LAYER M4 ;
		RECT 33.037 42.663 33.929 42.713 ;
		LAYER M4 ;
		RECT 33.037 43.925 33.929 43.975 ;
		LAYER M4 ;
		RECT 33.037 44.679 33.929 44.729 ;
		LAYER M4 ;
		RECT 33.037 45.941 33.929 45.991 ;
		LAYER M4 ;
		RECT 33.037 46.695 33.929 46.745 ;
		LAYER M4 ;
		RECT 33.037 60.821 33.929 60.871 ;
		LAYER M4 ;
		RECT 33.037 61.575 33.929 61.625 ;
		LAYER M4 ;
		RECT 33.037 62.837 33.929 62.887 ;
		LAYER M4 ;
		RECT 33.037 63.591 33.929 63.641 ;
		LAYER M4 ;
		RECT 33.037 64.853 33.929 64.903 ;
		LAYER M4 ;
		RECT 33.037 65.607 33.929 65.657 ;
		LAYER M4 ;
		RECT 33.037 66.869 33.929 66.919 ;
		LAYER M4 ;
		RECT 33.037 67.623 33.929 67.673 ;
		LAYER M4 ;
		RECT 33.037 68.885 33.929 68.935 ;
		LAYER M4 ;
		RECT 33.037 69.639 33.929 69.689 ;
		LAYER M4 ;
		RECT 33.037 70.901 33.929 70.951 ;
		LAYER M4 ;
		RECT 33.037 71.655 33.929 71.705 ;
		LAYER M4 ;
		RECT 33.037 72.917 33.929 72.967 ;
		LAYER M4 ;
		RECT 33.037 73.671 33.929 73.721 ;
		LAYER M4 ;
		RECT 33.037 74.933 33.929 74.983 ;
		LAYER M4 ;
		RECT 33.037 75.687 33.929 75.737 ;
		LAYER M4 ;
		RECT 33.037 76.949 33.929 76.999 ;
		LAYER M4 ;
		RECT 33.037 77.703 33.929 77.753 ;
		LAYER M4 ;
		RECT 33.037 78.965 33.929 79.015 ;
		LAYER M4 ;
		RECT 33.037 79.719 33.929 79.769 ;
		LAYER M4 ;
		RECT 33.037 80.981 33.929 81.031 ;
		LAYER M4 ;
		RECT 33.037 81.735 33.929 81.785 ;
		LAYER M4 ;
		RECT 33.037 82.997 33.929 83.047 ;
		LAYER M4 ;
		RECT 33.037 83.751 33.929 83.801 ;
		LAYER M4 ;
		RECT 33.037 85.013 33.929 85.063 ;
		LAYER M4 ;
		RECT 33.037 85.767 33.929 85.817 ;
		LAYER M4 ;
		RECT 33.037 87.029 33.929 87.079 ;
		LAYER M4 ;
		RECT 33.037 87.783 33.929 87.833 ;
		LAYER M4 ;
		RECT 33.037 89.045 33.929 89.095 ;
		LAYER M4 ;
		RECT 33.037 89.799 33.929 89.849 ;
		LAYER M4 ;
		RECT 33.037 91.061 33.929 91.111 ;
		LAYER M4 ;
		RECT 33.037 91.815 33.929 91.865 ;
		LAYER M4 ;
		RECT 33.037 93.077 33.929 93.127 ;
		LAYER M4 ;
		RECT 33.037 93.831 33.929 93.881 ;
		LAYER M4 ;
		RECT 33.037 95.093 33.929 95.143 ;
		LAYER M4 ;
		RECT 33.037 95.847 33.929 95.897 ;
		LAYER M4 ;
		RECT 33.037 97.109 33.929 97.159 ;
		LAYER M4 ;
		RECT 33.037 97.863 33.929 97.913 ;
		LAYER M4 ;
		RECT 33.037 99.125 33.929 99.175 ;
		LAYER M4 ;
		RECT 33.037 99.879 33.929 99.929 ;
		LAYER M4 ;
		RECT 33.037 101.141 33.929 101.191 ;
		LAYER M4 ;
		RECT 33.037 101.895 33.929 101.945 ;
		LAYER M4 ;
		RECT 33.037 103.157 33.929 103.207 ;
		LAYER M4 ;
		RECT 33.037 103.911 33.929 103.961 ;
		LAYER VIA1 ;
		RECT 0.000 0.000 43.025 105.552 ;
		LAYER VIA2 ;
		RECT 0.000 0.000 43.025 105.552 ;
	END
END TS1N16ADFPCLLLVTA512X45M4SWSHOD

END LIBRARY
